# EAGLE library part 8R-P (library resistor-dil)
DIL RESISTOR

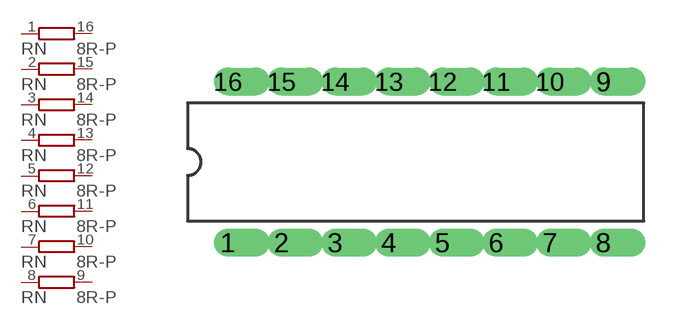
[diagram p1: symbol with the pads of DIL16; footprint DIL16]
Designator prefix RN; gates A=R1PV B=R1PV C=R1PV D=R1PV E=R1PV F=R1PV G=R1PV H=R1PV

## 8R-P  [DIL16]
1  A:1  pas
2  B:1  pas
3  C:1  pas
4  D:1  pas
5  E:1  pas
6  F:1  pas
7  G:1  pas
8  H:1  pas
9  H:2  pas
10  G:2  pas
11  F:2  pas
12  E:2  pas
13  D:2  pas
14  C:2  pas
15  B:2  pas
16  A:2  pas

## Footprint DIL16 (pad centres in mm)
Dual In Line
drill 0.813 offset: 1 -8.89,-3.81; 2 -6.35,-3.81; 3 -3.81,-3.81; 4 -1.27,-3.81; 5 1.27,-3.81; 6 3.81,-3.81; 7 6.35,-3.81; 8 8.89,-3.81; 9 8.89,3.81; 10 6.35,3.81; 11 3.81,3.81; 12 1.27,3.81; 13 -1.27,3.81; 14 -3.81,3.81; 15 -6.35,3.81; 16 -8.89,3.81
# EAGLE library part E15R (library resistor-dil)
DIL RESISTOR

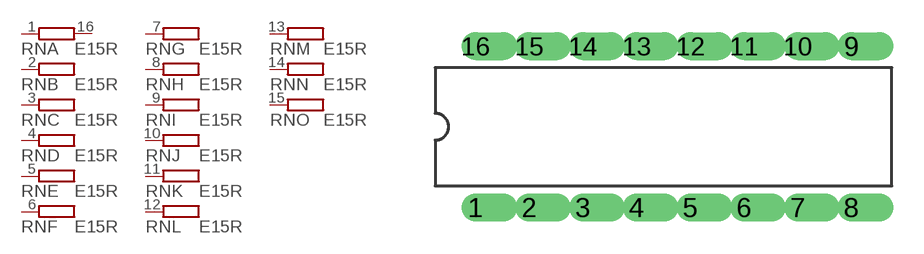
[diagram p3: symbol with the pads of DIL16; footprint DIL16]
Designator prefix RN; gates A=R1NV0 B=R1NVXX C=R1NVXX D=R1NVXX E=R1NVXX F=R1NVXX G=R1NVXX H=R1NVXX I=R1NVXX J=R1NVXX K=R1NVXX L=R1NVXX M=R1NVXX N=R1NVXX O=R1NVXX

## E15R  [DIL16]
1  A:1  pas
2  B:1  pas
3  C:1  pas
4  D:1  pas
5  E:1  pas
6  F:1  pas
7  G:1  pas
8  H:1  pas
9  I:1  pas
10  J:1  pas
11  K:1  pas
12  L:1  pas
13  M:1  pas
14  N:1  pas
15  O:1  pas
16  A:2  pas

## Footprint DIL16 (pad centres in mm)
Dual In Line
drill 0.813 offset: 1 -8.89,-3.81; 2 -6.35,-3.81; 3 -3.81,-3.81; 4 -1.27,-3.81; 5 1.27,-3.81; 6 3.81,-3.81; 7 6.35,-3.81; 8 8.89,-3.81; 9 8.89,3.81; 10 6.35,3.81; 11 3.81,3.81; 12 1.27,3.81; 13 -1.27,3.81; 14 -3.81,3.81; 15 -6.35,3.81; 16 -8.89,3.81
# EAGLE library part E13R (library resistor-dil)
DIL RESISTOR

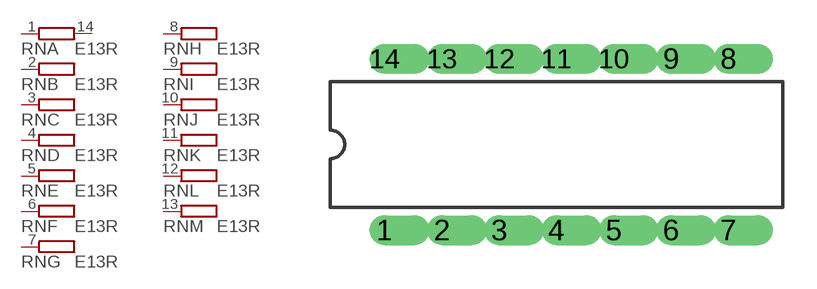
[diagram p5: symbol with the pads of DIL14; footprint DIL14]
Designator prefix RN; gates A=R1NV0 B=R1NVXX C=R1NVXX D=R1NVXX E=R1NVXX F=R1NVXX G=R1NVXX H=R1NVXX I=R1NVXX J=R1NVXX K=R1NVXX L=R1NVXX M=R1NVXX

## E13R  [DIL14]
1  A:1  pas
2  B:1  pas
3  C:1  pas
4  D:1  pas
5  E:1  pas
6  F:1  pas
7  G:1  pas
8  H:1  pas
9  I:1  pas
10  J:1  pas
11  K:1  pas
12  L:1  pas
13  M:1  pas
14  A:2  pas

## Footprint DIL14 (pad centres in mm)
Dual In Line
drill 0.813 offset: 1 -7.62,-3.81; 2 -5.08,-3.81; 3 -2.54,-3.81; 4 0,-3.81; 5 2.54,-3.81; 6 5.08,-3.81; 7 7.62,-3.81; 8 7.62,3.81; 9 5.08,3.81; 10 2.54,3.81; 11 0,3.81; 12 -2.54,3.81; 13 -5.08,3.81; 14 -7.62,3.81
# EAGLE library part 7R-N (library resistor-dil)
DIL RESISTOR

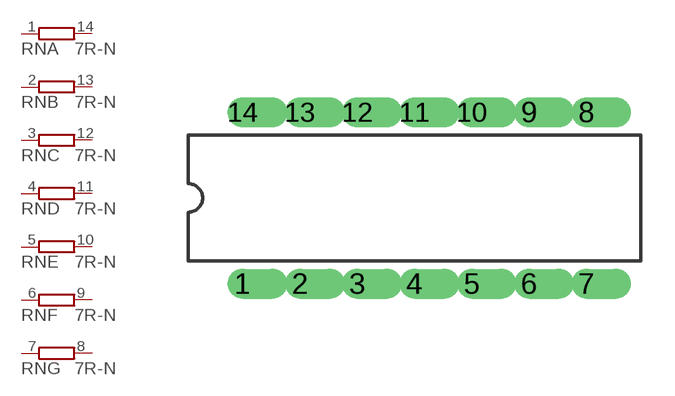
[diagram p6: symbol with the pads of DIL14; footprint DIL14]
Designator prefix RN; gates A=R1NV B=R1NV C=R1NV D=R1NV E=R1NV F=R1NV G=R1NV

## 7R-N  [DIL14]
1  A:1  pas
2  B:1  pas
3  C:1  pas
4  D:1  pas
5  E:1  pas
6  F:1  pas
7  G:1  pas
8  G:2  pas
9  F:2  pas
10  E:2  pas
11  D:2  pas
12  C:2  pas
13  B:2  pas
14  A:2  pas

## Footprint DIL14 (pad centres in mm)
Dual In Line
drill 0.813 offset: 1 -7.62,-3.81; 2 -5.08,-3.81; 3 -2.54,-3.81; 4 0,-3.81; 5 2.54,-3.81; 6 5.08,-3.81; 7 7.62,-3.81; 8 7.62,3.81; 9 5.08,3.81; 10 2.54,3.81; 11 0,3.81; 12 -2.54,3.81; 13 -5.08,3.81; 14 -7.62,3.81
